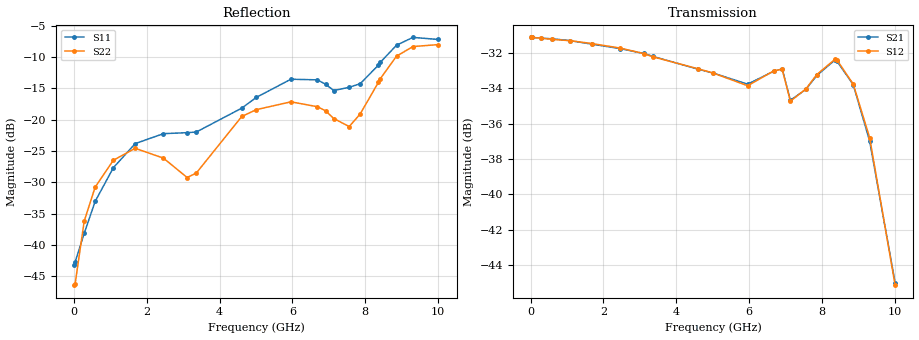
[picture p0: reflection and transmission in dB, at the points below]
! Device ID: PE43704
! Dir: z:\PE43704\PE43704_Char_1_20130516\PE43704\AMB\3p400V\30p25dB
! Serial: 14
! Insertion: A
! Impedance: 50 ohm
! Temp: Amb
! VDD: 3.400V
! Attenuation Step: 30.25dB
! IDD: 1.140633e-01mA
#  Hz  S  RI  R  50
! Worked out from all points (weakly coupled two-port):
!   401 points, 10 MHz to 10.01 GHz, reference 50 ohm
!   highest |S21| = -31.11 dB at 35 MHz (marker M1); lowest = -45.0 dB at 10.01 GHz (marker M2)
!   lowest |S11| = -43.2 dB at 10 MHz (marker M3), VSWR 1.01, Z = 50.7 + j0.0365 ohm
!   |S11| at or under -10 dB: start of sweep to 8.534 GHz
!   |S22| runs from -46.4 to -7.9 dB; largest |S21 - S12| = 0.00054
!   S11 on the Smith chart (normalised r, x): 10 MHz: 1.01, +0.00; 4.61 GHz: 0.80, +0.08; 8.41 GHz: 0.78, +0.48; 9.31 GHz: 0.51, +0.54; 10.01 GHz: 0.45, +0.33
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1e7  0.00693 0.00036  0.0278 -6.4e-05  0.0278 -6.41e-05  -0.00475 0.000448
3.5e7  0.00711 0.00154  0.0278 -0.000248  0.0278 -0.000239  -0.00451 0.00186
2.85e8  0.00395 0.0117  0.0276 -0.00183  0.0276 -0.00185  -0.00659 0.014
5.85e8  -0.00635 0.0213  0.0273 -0.00371  0.0272 -0.00368  -0.0153 0.0245
1.085e9  -0.0337 0.0238  0.0264 -0.00665  0.0264 -0.0066  -0.0378 0.0285
1.685e9  -0.0638 0.00785  0.0247 -0.00988  0.0248 -0.00992  -0.0573 0.0139
2.46e9  -0.0757 -0.015  0.0221 -0.0134  0.0222 -0.0134  -0.0492 -0.000604
3.11e9  -0.0771 -0.0152  0.0195 -0.0157  0.0194 -0.0158  -0.0333 0.00893
3.36e9  -0.079 -0.00877  0.0182 -0.0165  0.0182 -0.0164  -0.0332 0.0171
4.61e9  -0.1116 0.0525  0.0131 -0.0184  0.0132 -0.0184  -0.0863 0.0612
5.01e9  -0.1308 0.074  0.0123 -0.0183  0.0123 -0.0183  -0.1056 0.0569
5.96e9  -0.1808 0.1065  0.00862 -0.0186  0.00856 -0.0184  -0.1313 0.0441
6.685e9  -0.1809 0.1014  0.00759 -0.021  0.00743 -0.0211  -0.1217 0.0351
6.91e9  -0.1647 0.0981  0.00488 -0.0221  0.00466 -0.0221  -0.1107 0.0394
7.135e9  -0.1478 0.085  0.00364 -0.0181  0.00356 -0.018  -0.0913 0.0453
7.56e9  -0.1221 0.1336  0.00403 -0.0194  0.00431 -0.0194  -0.0589 0.0653
7.86e9  -0.0854 0.1731  0.00411 -0.0213  0.00429 -0.0214  -0.0519 0.0977
8.36e9  -0.0498 0.267  -0.00306 -0.0238  -0.00314 -0.0239  -0.0717 0.1844
8.41e9  -0.0504 0.2809  -0.00397 -0.0235  -0.00392 -0.0237  -0.0789 0.1959
8.86e9  -0.0894 0.3819  -0.0102 -0.0177  -0.01 -0.0179  -0.1439 0.2867
9.31e9  -0.17 0.4195  -0.00961 -0.0104  -0.00998 -0.0105  -0.2351 0.3015
1.001e10  -0.3134 0.3023  -0.00052 -0.00561  -0.000824 -0.00548  -0.3727 0.1355
